VERSION 5.7 ;
BUSBITCHARS "[]" ;
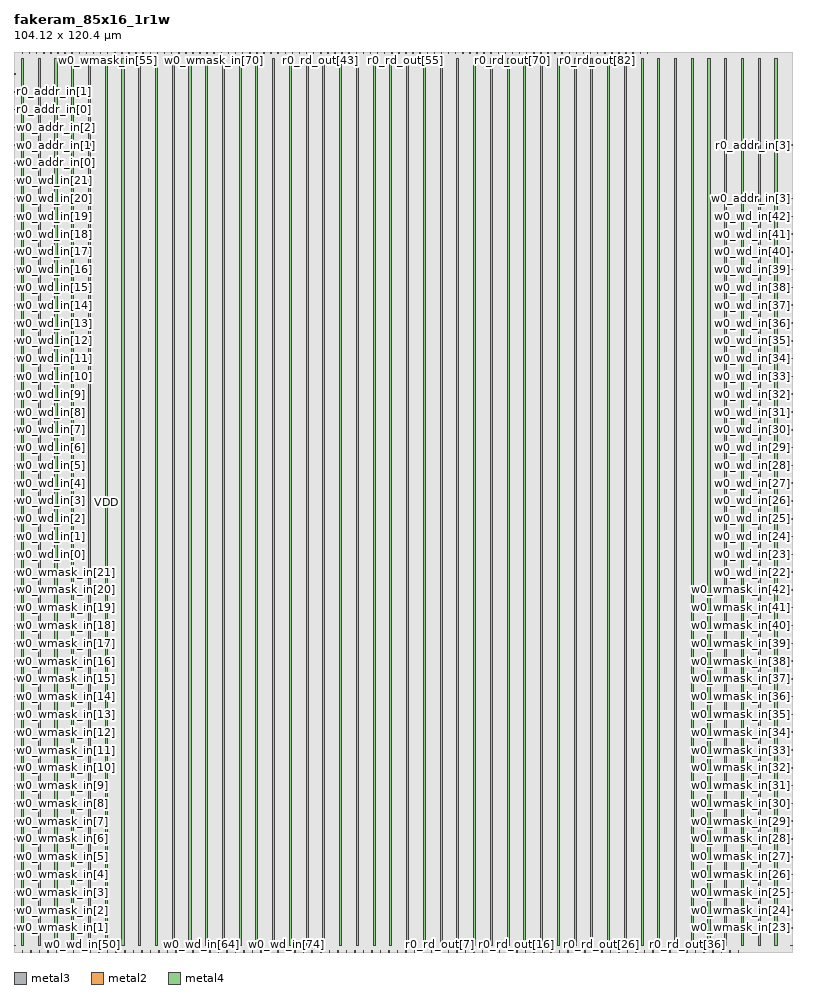
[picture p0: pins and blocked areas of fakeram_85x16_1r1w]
MACRO fakeram_85x16_1r1w
  FOREIGN fakeram_85x16_1r1w 0 0 ;
  SYMMETRY X Y R90 ;
  SIZE 104.120 BY 120.400 ;
  CLASS BLOCK ;
  PIN w0_wmask_in[0]
    DIRECTION INPUT ;
    USE SIGNAL ;
    SHAPE ABUTMENT ;
    PORT
      LAYER metal3 ;
      RECT 0.000 0.805 0.210 0.875 ;
    END
  END w0_wmask_in[0]
  PIN w0_wmask_in[1]
    DIRECTION INPUT ;
    USE SIGNAL ;
    SHAPE ABUTMENT ;
    PORT
      LAYER metal3 ;
      RECT 0.000 3.185 0.210 3.255 ;
    END
  END w0_wmask_in[1]
  PIN w0_wmask_in[2]
    DIRECTION INPUT ;
    USE SIGNAL ;
    SHAPE ABUTMENT ;
    PORT
      LAYER metal3 ;
      RECT 0.000 5.565 0.210 5.635 ;
    END
  END w0_wmask_in[2]
  PIN w0_wmask_in[3]
    DIRECTION INPUT ;
    USE SIGNAL ;
    SHAPE ABUTMENT ;
    PORT
      LAYER metal3 ;
      RECT 0.000 7.945 0.210 8.015 ;
    END
  END w0_wmask_in[3]
  PIN w0_wmask_in[4]
    DIRECTION INPUT ;
    USE SIGNAL ;
    SHAPE ABUTMENT ;
    PORT
      LAYER metal3 ;
      RECT 0.000 10.325 0.210 10.395 ;
    END
  END w0_wmask_in[4]
  PIN w0_wmask_in[5]
    DIRECTION INPUT ;
    USE SIGNAL ;
    SHAPE ABUTMENT ;
    PORT
      LAYER metal3 ;
      RECT 0.000 12.705 0.210 12.775 ;
    END
  END w0_wmask_in[5]
  PIN w0_wmask_in[6]
    DIRECTION INPUT ;
    USE SIGNAL ;
    SHAPE ABUTMENT ;
    PORT
      LAYER metal3 ;
      RECT 0.000 15.085 0.210 15.155 ;
    END
  END w0_wmask_in[6]
  PIN w0_wmask_in[7]
    DIRECTION INPUT ;
    USE SIGNAL ;
    SHAPE ABUTMENT ;
    PORT
      LAYER metal3 ;
      RECT 0.000 17.465 0.210 17.535 ;
    END
  END w0_wmask_in[7]
  PIN w0_wmask_in[8]
    DIRECTION INPUT ;
    USE SIGNAL ;
    SHAPE ABUTMENT ;
    PORT
      LAYER metal3 ;
      RECT 0.000 19.845 0.210 19.915 ;
    END
  END w0_wmask_in[8]
  PIN w0_wmask_in[9]
    DIRECTION INPUT ;
    USE SIGNAL ;
    SHAPE ABUTMENT ;
    PORT
      LAYER metal3 ;
      RECT 0.000 22.225 0.210 22.295 ;
    END
  END w0_wmask_in[9]
  PIN w0_wmask_in[10]
    DIRECTION INPUT ;
    USE SIGNAL ;
    SHAPE ABUTMENT ;
    PORT
      LAYER metal3 ;
      RECT 0.000 24.605 0.210 24.675 ;
    END
  END w0_wmask_in[10]
  PIN w0_wmask_in[11]
    DIRECTION INPUT ;
    USE SIGNAL ;
    SHAPE ABUTMENT ;
    PORT
      LAYER metal3 ;
      RECT 0.000 26.985 0.210 27.055 ;
    END
  END w0_wmask_in[11]
  PIN w0_wmask_in[12]
    DIRECTION INPUT ;
    USE SIGNAL ;
    SHAPE ABUTMENT ;
    PORT
      LAYER metal3 ;
      RECT 0.000 29.365 0.210 29.435 ;
    END
  END w0_wmask_in[12]
  PIN w0_wmask_in[13]
    DIRECTION INPUT ;
    USE SIGNAL ;
    SHAPE ABUTMENT ;
    PORT
      LAYER metal3 ;
      RECT 0.000 31.745 0.210 31.815 ;
    END
  END w0_wmask_in[13]
  PIN w0_wmask_in[14]
    DIRECTION INPUT ;
    USE SIGNAL ;
    SHAPE ABUTMENT ;
    PORT
      LAYER metal3 ;
      RECT 0.000 34.125 0.210 34.195 ;
    END
  END w0_wmask_in[14]
  PIN w0_wmask_in[15]
    DIRECTION INPUT ;
    USE SIGNAL ;
    SHAPE ABUTMENT ;
    PORT
      LAYER metal3 ;
      RECT 0.000 36.505 0.210 36.575 ;
    END
  END w0_wmask_in[15]
  PIN w0_wmask_in[16]
    DIRECTION INPUT ;
    USE SIGNAL ;
    SHAPE ABUTMENT ;
    PORT
      LAYER metal3 ;
      RECT 0.000 38.885 0.210 38.955 ;
    END
  END w0_wmask_in[16]
  PIN w0_wmask_in[17]
    DIRECTION INPUT ;
    USE SIGNAL ;
    SHAPE ABUTMENT ;
    PORT
      LAYER metal3 ;
      RECT 0.000 41.265 0.210 41.335 ;
    END
  END w0_wmask_in[17]
  PIN w0_wmask_in[18]
    DIRECTION INPUT ;
    USE SIGNAL ;
    SHAPE ABUTMENT ;
    PORT
      LAYER metal3 ;
      RECT 0.000 43.645 0.210 43.715 ;
    END
  END w0_wmask_in[18]
  PIN w0_wmask_in[19]
    DIRECTION INPUT ;
    USE SIGNAL ;
    SHAPE ABUTMENT ;
    PORT
      LAYER metal3 ;
      RECT 0.000 46.025 0.210 46.095 ;
    END
  END w0_wmask_in[19]
  PIN w0_wmask_in[20]
    DIRECTION INPUT ;
    USE SIGNAL ;
    SHAPE ABUTMENT ;
    PORT
      LAYER metal3 ;
      RECT 0.000 48.405 0.210 48.475 ;
    END
  END w0_wmask_in[20]
  PIN w0_wmask_in[21]
    DIRECTION INPUT ;
    USE SIGNAL ;
    SHAPE ABUTMENT ;
    PORT
      LAYER metal3 ;
      RECT 0.000 50.785 0.210 50.855 ;
    END
  END w0_wmask_in[21]
  PIN w0_wmask_in[22]
    DIRECTION INPUT ;
    USE SIGNAL ;
    SHAPE ABUTMENT ;
    PORT
      LAYER metal3 ;
      RECT 103.910 0.805 104.120 0.875 ;
    END
  END w0_wmask_in[22]
  PIN w0_wmask_in[23]
    DIRECTION INPUT ;
    USE SIGNAL ;
    SHAPE ABUTMENT ;
    PORT
      LAYER metal3 ;
      RECT 103.910 3.185 104.120 3.255 ;
    END
  END w0_wmask_in[23]
  PIN w0_wmask_in[24]
    DIRECTION INPUT ;
    USE SIGNAL ;
    SHAPE ABUTMENT ;
    PORT
      LAYER metal3 ;
      RECT 103.910 5.565 104.120 5.635 ;
    END
  END w0_wmask_in[24]
  PIN w0_wmask_in[25]
    DIRECTION INPUT ;
    USE SIGNAL ;
    SHAPE ABUTMENT ;
    PORT
      LAYER metal3 ;
      RECT 103.910 7.945 104.120 8.015 ;
    END
  END w0_wmask_in[25]
  PIN w0_wmask_in[26]
    DIRECTION INPUT ;
    USE SIGNAL ;
    SHAPE ABUTMENT ;
    PORT
      LAYER metal3 ;
      RECT 103.910 10.325 104.120 10.395 ;
    END
  END w0_wmask_in[26]
  PIN w0_wmask_in[27]
    DIRECTION INPUT ;
    USE SIGNAL ;
    SHAPE ABUTMENT ;
    PORT
      LAYER metal3 ;
      RECT 103.910 12.705 104.120 12.775 ;
    END
  END w0_wmask_in[27]
  PIN w0_wmask_in[28]
    DIRECTION INPUT ;
    USE SIGNAL ;
    SHAPE ABUTMENT ;
    PORT
      LAYER metal3 ;
      RECT 103.910 15.085 104.120 15.155 ;
    END
  END w0_wmask_in[28]
  PIN w0_wmask_in[29]
    DIRECTION INPUT ;
    USE SIGNAL ;
    SHAPE ABUTMENT ;
    PORT
      LAYER metal3 ;
      RECT 103.910 17.465 104.120 17.535 ;
    END
  END w0_wmask_in[29]
  PIN w0_wmask_in[30]
    DIRECTION INPUT ;
    USE SIGNAL ;
    SHAPE ABUTMENT ;
    PORT
      LAYER metal3 ;
      RECT 103.910 19.845 104.120 19.915 ;
    END
  END w0_wmask_in[30]
  PIN w0_wmask_in[31]
    DIRECTION INPUT ;
    USE SIGNAL ;
    SHAPE ABUTMENT ;
    PORT
      LAYER metal3 ;
      RECT 103.910 22.225 104.120 22.295 ;
    END
  END w0_wmask_in[31]
  PIN w0_wmask_in[32]
    DIRECTION INPUT ;
    USE SIGNAL ;
    SHAPE ABUTMENT ;
    PORT
      LAYER metal3 ;
      RECT 103.910 24.605 104.120 24.675 ;
    END
  END w0_wmask_in[32]
  PIN w0_wmask_in[33]
    DIRECTION INPUT ;
    USE SIGNAL ;
    SHAPE ABUTMENT ;
    PORT
      LAYER metal3 ;
      RECT 103.910 26.985 104.120 27.055 ;
    END
  END w0_wmask_in[33]
  PIN w0_wmask_in[34]
    DIRECTION INPUT ;
    USE SIGNAL ;
    SHAPE ABUTMENT ;
    PORT
      LAYER metal3 ;
      RECT 103.910 29.365 104.120 29.435 ;
    END
  END w0_wmask_in[34]
  PIN w0_wmask_in[35]
    DIRECTION INPUT ;
    USE SIGNAL ;
    SHAPE ABUTMENT ;
    PORT
      LAYER metal3 ;
      RECT 103.910 31.745 104.120 31.815 ;
    END
  END w0_wmask_in[35]
  PIN w0_wmask_in[36]
    DIRECTION INPUT ;
    USE SIGNAL ;
    SHAPE ABUTMENT ;
    PORT
      LAYER metal3 ;
      RECT 103.910 34.125 104.120 34.195 ;
    END
  END w0_wmask_in[36]
  PIN w0_wmask_in[37]
    DIRECTION INPUT ;
    USE SIGNAL ;
    SHAPE ABUTMENT ;
    PORT
      LAYER metal3 ;
      RECT 103.910 36.505 104.120 36.575 ;
    END
  END w0_wmask_in[37]
  PIN w0_wmask_in[38]
    DIRECTION INPUT ;
    USE SIGNAL ;
    SHAPE ABUTMENT ;
    PORT
      LAYER metal3 ;
      RECT 103.910 38.885 104.120 38.955 ;
    END
  END w0_wmask_in[38]
  PIN w0_wmask_in[39]
    DIRECTION INPUT ;
    USE SIGNAL ;
    SHAPE ABUTMENT ;
    PORT
      LAYER metal3 ;
      RECT 103.910 41.265 104.120 41.335 ;
    END
  END w0_wmask_in[39]
  PIN w0_wmask_in[40]
    DIRECTION INPUT ;
    USE SIGNAL ;
    SHAPE ABUTMENT ;
    PORT
      LAYER metal3 ;
      RECT 103.910 43.645 104.120 43.715 ;
    END
  END w0_wmask_in[40]
  PIN w0_wmask_in[41]
    DIRECTION INPUT ;
    USE SIGNAL ;
    SHAPE ABUTMENT ;
    PORT
      LAYER metal3 ;
      RECT 103.910 46.025 104.120 46.095 ;
    END
  END w0_wmask_in[41]
  PIN w0_wmask_in[42]
    DIRECTION INPUT ;
    USE SIGNAL ;
    SHAPE ABUTMENT ;
    PORT
      LAYER metal3 ;
      RECT 103.910 48.405 104.120 48.475 ;
    END
  END w0_wmask_in[42]
  PIN w0_wmask_in[43]
    DIRECTION INPUT ;
    USE SIGNAL ;
    SHAPE ABUTMENT ;
    PORT
      LAYER metal2 ;
      RECT 1.105 120.190 1.175 120.400 ;
    END
  END w0_wmask_in[43]
  PIN w0_wmask_in[44]
    DIRECTION INPUT ;
    USE SIGNAL ;
    SHAPE ABUTMENT ;
    PORT
      LAYER metal2 ;
      RECT 2.055 120.190 2.125 120.400 ;
    END
  END w0_wmask_in[44]
  PIN w0_wmask_in[45]
    DIRECTION INPUT ;
    USE SIGNAL ;
    SHAPE ABUTMENT ;
    PORT
      LAYER metal2 ;
      RECT 3.005 120.190 3.075 120.400 ;
    END
  END w0_wmask_in[45]
  PIN w0_wmask_in[46]
    DIRECTION INPUT ;
    USE SIGNAL ;
    SHAPE ABUTMENT ;
    PORT
      LAYER metal2 ;
      RECT 3.955 120.190 4.025 120.400 ;
    END
  END w0_wmask_in[46]
  PIN w0_wmask_in[47]
    DIRECTION INPUT ;
    USE SIGNAL ;
    SHAPE ABUTMENT ;
    PORT
      LAYER metal2 ;
      RECT 4.905 120.190 4.975 120.400 ;
    END
  END w0_wmask_in[47]
  PIN w0_wmask_in[48]
    DIRECTION INPUT ;
    USE SIGNAL ;
    SHAPE ABUTMENT ;
    PORT
      LAYER metal2 ;
      RECT 5.855 120.190 5.925 120.400 ;
    END
  END w0_wmask_in[48]
  PIN w0_wmask_in[49]
    DIRECTION INPUT ;
    USE SIGNAL ;
    SHAPE ABUTMENT ;
    PORT
      LAYER metal2 ;
      RECT 6.805 120.190 6.875 120.400 ;
    END
  END w0_wmask_in[49]
  PIN w0_wmask_in[50]
    DIRECTION INPUT ;
    USE SIGNAL ;
    SHAPE ABUTMENT ;
    PORT
      LAYER metal2 ;
      RECT 7.755 120.190 7.825 120.400 ;
    END
  END w0_wmask_in[50]
  PIN w0_wmask_in[51]
    DIRECTION INPUT ;
    USE SIGNAL ;
    SHAPE ABUTMENT ;
    PORT
      LAYER metal2 ;
      RECT 8.705 120.190 8.775 120.400 ;
    END
  END w0_wmask_in[51]
  PIN w0_wmask_in[52]
    DIRECTION INPUT ;
    USE SIGNAL ;
    SHAPE ABUTMENT ;
    PORT
      LAYER metal2 ;
      RECT 9.655 120.190 9.725 120.400 ;
    END
  END w0_wmask_in[52]
  PIN w0_wmask_in[53]
    DIRECTION INPUT ;
    USE SIGNAL ;
    SHAPE ABUTMENT ;
    PORT
      LAYER metal2 ;
      RECT 10.605 120.190 10.675 120.400 ;
    END
  END w0_wmask_in[53]
  PIN w0_wmask_in[54]
    DIRECTION INPUT ;
    USE SIGNAL ;
    SHAPE ABUTMENT ;
    PORT
      LAYER metal2 ;
      RECT 11.555 120.190 11.625 120.400 ;
    END
  END w0_wmask_in[54]
  PIN w0_wmask_in[55]
    DIRECTION INPUT ;
    USE SIGNAL ;
    SHAPE ABUTMENT ;
    PORT
      LAYER metal2 ;
      RECT 12.505 120.190 12.575 120.400 ;
    END
  END w0_wmask_in[55]
  PIN w0_wmask_in[56]
    DIRECTION INPUT ;
    USE SIGNAL ;
    SHAPE ABUTMENT ;
    PORT
      LAYER metal2 ;
      RECT 13.455 120.190 13.525 120.400 ;
    END
  END w0_wmask_in[56]
  PIN w0_wmask_in[57]
    DIRECTION INPUT ;
    USE SIGNAL ;
    SHAPE ABUTMENT ;
    PORT
      LAYER metal2 ;
      RECT 14.405 120.190 14.475 120.400 ;
    END
  END w0_wmask_in[57]
  PIN w0_wmask_in[58]
    DIRECTION INPUT ;
    USE SIGNAL ;
    SHAPE ABUTMENT ;
    PORT
      LAYER metal2 ;
      RECT 15.355 120.190 15.425 120.400 ;
    END
  END w0_wmask_in[58]
  PIN w0_wmask_in[59]
    DIRECTION INPUT ;
    USE SIGNAL ;
    SHAPE ABUTMENT ;
    PORT
      LAYER metal2 ;
      RECT 16.305 120.190 16.375 120.400 ;
    END
  END w0_wmask_in[59]
  PIN w0_wmask_in[60]
    DIRECTION INPUT ;
    USE SIGNAL ;
    SHAPE ABUTMENT ;
    PORT
      LAYER metal2 ;
      RECT 17.255 120.190 17.325 120.400 ;
    END
  END w0_wmask_in[60]
  PIN w0_wmask_in[61]
    DIRECTION INPUT ;
    USE SIGNAL ;
    SHAPE ABUTMENT ;
    PORT
      LAYER metal2 ;
      RECT 18.205 120.190 18.275 120.400 ;
    END
  END w0_wmask_in[61]
  PIN w0_wmask_in[62]
    DIRECTION INPUT ;
    USE SIGNAL ;
    SHAPE ABUTMENT ;
    PORT
      LAYER metal2 ;
      RECT 19.155 120.190 19.225 120.400 ;
    END
  END w0_wmask_in[62]
  PIN w0_wmask_in[63]
    DIRECTION INPUT ;
    USE SIGNAL ;
    SHAPE ABUTMENT ;
    PORT
      LAYER metal2 ;
      RECT 20.105 120.190 20.175 120.400 ;
    END
  END w0_wmask_in[63]
  PIN w0_wmask_in[64]
    DIRECTION INPUT ;
    USE SIGNAL ;
    SHAPE ABUTMENT ;
    PORT
      LAYER metal2 ;
      RECT 21.055 120.190 21.125 120.400 ;
    END
  END w0_wmask_in[64]
  PIN w0_wmask_in[65]
    DIRECTION INPUT ;
    USE SIGNAL ;
    SHAPE ABUTMENT ;
    PORT
      LAYER metal2 ;
      RECT 22.005 120.190 22.075 120.400 ;
    END
  END w0_wmask_in[65]
  PIN w0_wmask_in[66]
    DIRECTION INPUT ;
    USE SIGNAL ;
    SHAPE ABUTMENT ;
    PORT
      LAYER metal2 ;
      RECT 22.955 120.190 23.025 120.400 ;
    END
  END w0_wmask_in[66]
  PIN w0_wmask_in[67]
    DIRECTION INPUT ;
    USE SIGNAL ;
    SHAPE ABUTMENT ;
    PORT
      LAYER metal2 ;
      RECT 23.905 120.190 23.975 120.400 ;
    END
  END w0_wmask_in[67]
  PIN w0_wmask_in[68]
    DIRECTION INPUT ;
    USE SIGNAL ;
    SHAPE ABUTMENT ;
    PORT
      LAYER metal2 ;
      RECT 24.855 120.190 24.925 120.400 ;
    END
  END w0_wmask_in[68]
  PIN w0_wmask_in[69]
    DIRECTION INPUT ;
    USE SIGNAL ;
    SHAPE ABUTMENT ;
    PORT
      LAYER metal2 ;
      RECT 25.805 120.190 25.875 120.400 ;
    END
  END w0_wmask_in[69]
  PIN w0_wmask_in[70]
    DIRECTION INPUT ;
    USE SIGNAL ;
    SHAPE ABUTMENT ;
    PORT
      LAYER metal2 ;
      RECT 26.755 120.190 26.825 120.400 ;
    END
  END w0_wmask_in[70]
  PIN w0_wmask_in[71]
    DIRECTION INPUT ;
    USE SIGNAL ;
    SHAPE ABUTMENT ;
    PORT
      LAYER metal2 ;
      RECT 27.705 120.190 27.775 120.400 ;
    END
  END w0_wmask_in[71]
  PIN w0_wmask_in[72]
    DIRECTION INPUT ;
    USE SIGNAL ;
    SHAPE ABUTMENT ;
    PORT
      LAYER metal2 ;
      RECT 28.655 120.190 28.725 120.400 ;
    END
  END w0_wmask_in[72]
  PIN w0_wmask_in[73]
    DIRECTION INPUT ;
    USE SIGNAL ;
    SHAPE ABUTMENT ;
    PORT
      LAYER metal2 ;
      RECT 29.605 120.190 29.675 120.400 ;
    END
  END w0_wmask_in[73]
  PIN w0_wmask_in[74]
    DIRECTION INPUT ;
    USE SIGNAL ;
    SHAPE ABUTMENT ;
    PORT
      LAYER metal2 ;
      RECT 30.555 120.190 30.625 120.400 ;
    END
  END w0_wmask_in[74]
  PIN w0_wmask_in[75]
    DIRECTION INPUT ;
    USE SIGNAL ;
    SHAPE ABUTMENT ;
    PORT
      LAYER metal2 ;
      RECT 31.505 120.190 31.575 120.400 ;
    END
  END w0_wmask_in[75]
  PIN w0_wmask_in[76]
    DIRECTION INPUT ;
    USE SIGNAL ;
    SHAPE ABUTMENT ;
    PORT
      LAYER metal2 ;
      RECT 32.455 120.190 32.525 120.400 ;
    END
  END w0_wmask_in[76]
  PIN w0_wmask_in[77]
    DIRECTION INPUT ;
    USE SIGNAL ;
    SHAPE ABUTMENT ;
    PORT
      LAYER metal2 ;
      RECT 33.405 120.190 33.475 120.400 ;
    END
  END w0_wmask_in[77]
  PIN w0_wmask_in[78]
    DIRECTION INPUT ;
    USE SIGNAL ;
    SHAPE ABUTMENT ;
    PORT
      LAYER metal2 ;
      RECT 34.355 120.190 34.425 120.400 ;
    END
  END w0_wmask_in[78]
  PIN w0_wmask_in[79]
    DIRECTION INPUT ;
    USE SIGNAL ;
    SHAPE ABUTMENT ;
    PORT
      LAYER metal2 ;
      RECT 35.305 120.190 35.375 120.400 ;
    END
  END w0_wmask_in[79]
  PIN w0_wmask_in[80]
    DIRECTION INPUT ;
    USE SIGNAL ;
    SHAPE ABUTMENT ;
    PORT
      LAYER metal2 ;
      RECT 36.255 120.190 36.325 120.400 ;
    END
  END w0_wmask_in[80]
  PIN w0_wmask_in[81]
    DIRECTION INPUT ;
    USE SIGNAL ;
    SHAPE ABUTMENT ;
    PORT
      LAYER metal2 ;
      RECT 37.205 120.190 37.275 120.400 ;
    END
  END w0_wmask_in[81]
  PIN w0_wmask_in[82]
    DIRECTION INPUT ;
    USE SIGNAL ;
    SHAPE ABUTMENT ;
    PORT
      LAYER metal2 ;
      RECT 38.155 120.190 38.225 120.400 ;
    END
  END w0_wmask_in[82]
  PIN w0_wmask_in[83]
    DIRECTION INPUT ;
    USE SIGNAL ;
    SHAPE ABUTMENT ;
    PORT
      LAYER metal2 ;
      RECT 39.105 120.190 39.175 120.400 ;
    END
  END w0_wmask_in[83]
  PIN w0_wmask_in[84]
    DIRECTION INPUT ;
    USE SIGNAL ;
    SHAPE ABUTMENT ;
    PORT
      LAYER metal2 ;
      RECT 40.055 120.190 40.125 120.400 ;
    END
  END w0_wmask_in[84]
  PIN w0_wd_in[0]
    DIRECTION INPUT ;
    USE SIGNAL ;
    SHAPE ABUTMENT ;
    PORT
      LAYER metal3 ;
      RECT 0.000 53.165 0.210 53.235 ;
    END
  END w0_wd_in[0]
  PIN w0_wd_in[1]
    DIRECTION INPUT ;
    USE SIGNAL ;
    SHAPE ABUTMENT ;
    PORT
      LAYER metal3 ;
      RECT 0.000 55.545 0.210 55.615 ;
    END
  END w0_wd_in[1]
  PIN w0_wd_in[2]
    DIRECTION INPUT ;
    USE SIGNAL ;
    SHAPE ABUTMENT ;
    PORT
      LAYER metal3 ;
      RECT 0.000 57.925 0.210 57.995 ;
    END
  END w0_wd_in[2]
  PIN w0_wd_in[3]
    DIRECTION INPUT ;
    USE SIGNAL ;
    SHAPE ABUTMENT ;
    PORT
      LAYER metal3 ;
      RECT 0.000 60.305 0.210 60.375 ;
    END
  END w0_wd_in[3]
  PIN w0_wd_in[4]
    DIRECTION INPUT ;
    USE SIGNAL ;
    SHAPE ABUTMENT ;
    PORT
      LAYER metal3 ;
      RECT 0.000 62.685 0.210 62.755 ;
    END
  END w0_wd_in[4]
  PIN w0_wd_in[5]
    DIRECTION INPUT ;
    USE SIGNAL ;
    SHAPE ABUTMENT ;
    PORT
      LAYER metal3 ;
      RECT 0.000 65.065 0.210 65.135 ;
    END
  END w0_wd_in[5]
  PIN w0_wd_in[6]
    DIRECTION INPUT ;
    USE SIGNAL ;
    SHAPE ABUTMENT ;
    PORT
      LAYER metal3 ;
      RECT 0.000 67.445 0.210 67.515 ;
    END
  END w0_wd_in[6]
  PIN w0_wd_in[7]
    DIRECTION INPUT ;
    USE SIGNAL ;
    SHAPE ABUTMENT ;
    PORT
      LAYER metal3 ;
      RECT 0.000 69.825 0.210 69.895 ;
    END
  END w0_wd_in[7]
  PIN w0_wd_in[8]
    DIRECTION INPUT ;
    USE SIGNAL ;
    SHAPE ABUTMENT ;
    PORT
      LAYER metal3 ;
      RECT 0.000 72.205 0.210 72.275 ;
    END
  END w0_wd_in[8]
  PIN w0_wd_in[9]
    DIRECTION INPUT ;
    USE SIGNAL ;
    SHAPE ABUTMENT ;
    PORT
      LAYER metal3 ;
      RECT 0.000 74.585 0.210 74.655 ;
    END
  END w0_wd_in[9]
  PIN w0_wd_in[10]
    DIRECTION INPUT ;
    USE SIGNAL ;
    SHAPE ABUTMENT ;
    PORT
      LAYER metal3 ;
      RECT 0.000 76.965 0.210 77.035 ;
    END
  END w0_wd_in[10]
  PIN w0_wd_in[11]
    DIRECTION INPUT ;
    USE SIGNAL ;
    SHAPE ABUTMENT ;
    PORT
      LAYER metal3 ;
      RECT 0.000 79.345 0.210 79.415 ;
    END
  END w0_wd_in[11]
  PIN w0_wd_in[12]
    DIRECTION INPUT ;
    USE SIGNAL ;
    SHAPE ABUTMENT ;
    PORT
      LAYER metal3 ;
      RECT 0.000 81.725 0.210 81.795 ;
    END
  END w0_wd_in[12]
  PIN w0_wd_in[13]
    DIRECTION INPUT ;
    USE SIGNAL ;
    SHAPE ABUTMENT ;
    PORT
      LAYER metal3 ;
      RECT 0.000 84.105 0.210 84.175 ;
    END
  END w0_wd_in[13]
  PIN w0_wd_in[14]
    DIRECTION INPUT ;
    USE SIGNAL ;
    SHAPE ABUTMENT ;
    PORT
      LAYER metal3 ;
      RECT 0.000 86.485 0.210 86.555 ;
    END
  END w0_wd_in[14]
  PIN w0_wd_in[15]
    DIRECTION INPUT ;
    USE SIGNAL ;
    SHAPE ABUTMENT ;
    PORT
      LAYER metal3 ;
      RECT 0.000 88.865 0.210 88.935 ;
    END
  END w0_wd_in[15]
  PIN w0_wd_in[16]
    DIRECTION INPUT ;
    USE SIGNAL ;
    SHAPE ABUTMENT ;
    PORT
      LAYER metal3 ;
      RECT 0.000 91.245 0.210 91.315 ;
    END
  END w0_wd_in[16]
  PIN w0_wd_in[17]
    DIRECTION INPUT ;
    USE SIGNAL ;
    SHAPE ABUTMENT ;
    PORT
      LAYER metal3 ;
      RECT 0.000 93.625 0.210 93.695 ;
    END
  END w0_wd_in[17]
  PIN w0_wd_in[18]
    DIRECTION INPUT ;
    USE SIGNAL ;
    SHAPE ABUTMENT ;
    PORT
      LAYER metal3 ;
      RECT 0.000 96.005 0.210 96.075 ;
    END
  END w0_wd_in[18]
  PIN w0_wd_in[19]
    DIRECTION INPUT ;
    USE SIGNAL ;
    SHAPE ABUTMENT ;
    PORT
      LAYER metal3 ;
      RECT 0.000 98.385 0.210 98.455 ;
    END
  END w0_wd_in[19]
  PIN w0_wd_in[20]
    DIRECTION INPUT ;
    USE SIGNAL ;
    SHAPE ABUTMENT ;
    PORT
      LAYER metal3 ;
      RECT 0.000 100.765 0.210 100.835 ;
    END
  END w0_wd_in[20]
  PIN w0_wd_in[21]
    DIRECTION INPUT ;
    USE SIGNAL ;
    SHAPE ABUTMENT ;
    PORT
      LAYER metal3 ;
      RECT 0.000 103.145 0.210 103.215 ;
    END
  END w0_wd_in[21]
  PIN w0_wd_in[22]
    DIRECTION INPUT ;
    USE SIGNAL ;
    SHAPE ABUTMENT ;
    PORT
      LAYER metal3 ;
      RECT 103.910 50.785 104.120 50.855 ;
    END
  END w0_wd_in[22]
  PIN w0_wd_in[23]
    DIRECTION INPUT ;
    USE SIGNAL ;
    SHAPE ABUTMENT ;
    PORT
      LAYER metal3 ;
      RECT 103.910 53.165 104.120 53.235 ;
    END
  END w0_wd_in[23]
  PIN w0_wd_in[24]
    DIRECTION INPUT ;
    USE SIGNAL ;
    SHAPE ABUTMENT ;
    PORT
      LAYER metal3 ;
      RECT 103.910 55.545 104.120 55.615 ;
    END
  END w0_wd_in[24]
  PIN w0_wd_in[25]
    DIRECTION INPUT ;
    USE SIGNAL ;
    SHAPE ABUTMENT ;
    PORT
      LAYER metal3 ;
      RECT 103.910 57.925 104.120 57.995 ;
    END
  END w0_wd_in[25]
  PIN w0_wd_in[26]
    DIRECTION INPUT ;
    USE SIGNAL ;
    SHAPE ABUTMENT ;
    PORT
      LAYER metal3 ;
      RECT 103.910 60.305 104.120 60.375 ;
    END
  END w0_wd_in[26]
  PIN w0_wd_in[27]
    DIRECTION INPUT ;
    USE SIGNAL ;
    SHAPE ABUTMENT ;
    PORT
      LAYER metal3 ;
      RECT 103.910 62.685 104.120 62.755 ;
    END
  END w0_wd_in[27]
  PIN w0_wd_in[28]
    DIRECTION INPUT ;
    USE SIGNAL ;
    SHAPE ABUTMENT ;
    PORT
      LAYER metal3 ;
      RECT 103.910 65.065 104.120 65.135 ;
    END
  END w0_wd_in[28]
  PIN w0_wd_in[29]
    DIRECTION INPUT ;
    USE SIGNAL ;
    SHAPE ABUTMENT ;
    PORT
      LAYER metal3 ;
      RECT 103.910 67.445 104.120 67.515 ;
    END
  END w0_wd_in[29]
  PIN w0_wd_in[30]
    DIRECTION INPUT ;
    USE SIGNAL ;
    SHAPE ABUTMENT ;
    PORT
      LAYER metal3 ;
      RECT 103.910 69.825 104.120 69.895 ;
    END
  END w0_wd_in[30]
  PIN w0_wd_in[31]
    DIRECTION INPUT ;
    USE SIGNAL ;
    SHAPE ABUTMENT ;
    PORT
      LAYER metal3 ;
      RECT 103.910 72.205 104.120 72.275 ;
    END
  END w0_wd_in[31]
  PIN w0_wd_in[32]
    DIRECTION INPUT ;
    USE SIGNAL ;
    SHAPE ABUTMENT ;
    PORT
      LAYER metal3 ;
      RECT 103.910 74.585 104.120 74.655 ;
    END
  END w0_wd_in[32]
  PIN w0_wd_in[33]
    DIRECTION INPUT ;
    USE SIGNAL ;
    SHAPE ABUTMENT ;
    PORT
      LAYER metal3 ;
      RECT 103.910 76.965 104.120 77.035 ;
    END
  END w0_wd_in[33]
  PIN w0_wd_in[34]
    DIRECTION INPUT ;
    USE SIGNAL ;
    SHAPE ABUTMENT ;
    PORT
      LAYER metal3 ;
      RECT 103.910 79.345 104.120 79.415 ;
    END
  END w0_wd_in[34]
  PIN w0_wd_in[35]
    DIRECTION INPUT ;
    USE SIGNAL ;
    SHAPE ABUTMENT ;
    PORT
      LAYER metal3 ;
      RECT 103.910 81.725 104.120 81.795 ;
    END
  END w0_wd_in[35]
  PIN w0_wd_in[36]
    DIRECTION INPUT ;
    USE SIGNAL ;
    SHAPE ABUTMENT ;
    PORT
      LAYER metal3 ;
      RECT 103.910 84.105 104.120 84.175 ;
    END
  END w0_wd_in[36]
  PIN w0_wd_in[37]
    DIRECTION INPUT ;
    USE SIGNAL ;
    SHAPE ABUTMENT ;
    PORT
      LAYER metal3 ;
      RECT 103.910 86.485 104.120 86.555 ;
    END
  END w0_wd_in[37]
  PIN w0_wd_in[38]
    DIRECTION INPUT ;
    USE SIGNAL ;
    SHAPE ABUTMENT ;
    PORT
      LAYER metal3 ;
      RECT 103.910 88.865 104.120 88.935 ;
    END
  END w0_wd_in[38]
  PIN w0_wd_in[39]
    DIRECTION INPUT ;
    USE SIGNAL ;
    SHAPE ABUTMENT ;
    PORT
      LAYER metal3 ;
      RECT 103.910 91.245 104.120 91.315 ;
    END
  END w0_wd_in[39]
  PIN w0_wd_in[40]
    DIRECTION INPUT ;
    USE SIGNAL ;
    SHAPE ABUTMENT ;
    PORT
      LAYER metal3 ;
      RECT 103.910 93.625 104.120 93.695 ;
    END
  END w0_wd_in[40]
  PIN w0_wd_in[41]
    DIRECTION INPUT ;
    USE SIGNAL ;
    SHAPE ABUTMENT ;
    PORT
      LAYER metal3 ;
      RECT 103.910 96.005 104.120 96.075 ;
    END
  END w0_wd_in[41]
  PIN w0_wd_in[42]
    DIRECTION INPUT ;
    USE SIGNAL ;
    SHAPE ABUTMENT ;
    PORT
      LAYER metal3 ;
      RECT 103.910 98.385 104.120 98.455 ;
    END
  END w0_wd_in[42]
  PIN w0_wd_in[43]
    DIRECTION OUTPUT ;
    USE SIGNAL ;
    SHAPE ABUTMENT ;
    PORT
      LAYER metal2 ;
      RECT 1.105 0.000 1.175 0.210 ;
    END
  END w0_wd_in[43]
  PIN w0_wd_in[44]
    DIRECTION OUTPUT ;
    USE SIGNAL ;
    SHAPE ABUTMENT ;
    PORT
      LAYER metal2 ;
      RECT 2.245 0.000 2.315 0.210 ;
    END
  END w0_wd_in[44]
  PIN w0_wd_in[45]
    DIRECTION OUTPUT ;
    USE SIGNAL ;
    SHAPE ABUTMENT ;
    PORT
      LAYER metal2 ;
      RECT 3.385 0.000 3.455 0.210 ;
    END
  END w0_wd_in[45]
  PIN w0_wd_in[46]
    DIRECTION OUTPUT ;
    USE SIGNAL ;
    SHAPE ABUTMENT ;
    PORT
      LAYER metal2 ;
      RECT 4.525 0.000 4.595 0.210 ;
    END
  END w0_wd_in[46]
  PIN w0_wd_in[47]
    DIRECTION OUTPUT ;
    USE SIGNAL ;
    SHAPE ABUTMENT ;
    PORT
      LAYER metal2 ;
      RECT 5.665 0.000 5.735 0.210 ;
    END
  END w0_wd_in[47]
  PIN w0_wd_in[48]
    DIRECTION OUTPUT ;
    USE SIGNAL ;
    SHAPE ABUTMENT ;
    PORT
      LAYER metal2 ;
      RECT 6.805 0.000 6.875 0.210 ;
    END
  END w0_wd_in[48]
  PIN w0_wd_in[49]
    DIRECTION OUTPUT ;
    USE SIGNAL ;
    SHAPE ABUTMENT ;
    PORT
      LAYER metal2 ;
      RECT 7.945 0.000 8.015 0.210 ;
    END
  END w0_wd_in[49]
  PIN w0_wd_in[50]
    DIRECTION OUTPUT ;
    USE SIGNAL ;
    SHAPE ABUTMENT ;
    PORT
      LAYER metal2 ;
      RECT 9.085 0.000 9.155 0.210 ;
    END
  END w0_wd_in[50]
  PIN w0_wd_in[51]
    DIRECTION OUTPUT ;
    USE SIGNAL ;
    SHAPE ABUTMENT ;
    PORT
      LAYER metal2 ;
      RECT 10.225 0.000 10.295 0.210 ;
    END
  END w0_wd_in[51]
  PIN w0_wd_in[52]
    DIRECTION OUTPUT ;
    USE SIGNAL ;
    SHAPE ABUTMENT ;
    PORT
      LAYER metal2 ;
      RECT 11.365 0.000 11.435 0.210 ;
    END
  END w0_wd_in[52]
  PIN w0_wd_in[53]
    DIRECTION OUTPUT ;
    USE SIGNAL ;
    SHAPE ABUTMENT ;
    PORT
      LAYER metal2 ;
      RECT 12.505 0.000 12.575 0.210 ;
    END
  END w0_wd_in[53]
  PIN w0_wd_in[54]
    DIRECTION OUTPUT ;
    USE SIGNAL ;
    SHAPE ABUTMENT ;
    PORT
      LAYER metal2 ;
      RECT 13.645 0.000 13.715 0.210 ;
    END
  END w0_wd_in[54]
  PIN w0_wd_in[55]
    DIRECTION OUTPUT ;
    USE SIGNAL ;
    SHAPE ABUTMENT ;
    PORT
      LAYER metal2 ;
      RECT 14.785 0.000 14.855 0.210 ;
    END
  END w0_wd_in[55]
  PIN w0_wd_in[56]
    DIRECTION OUTPUT ;
    USE SIGNAL ;
    SHAPE ABUTMENT ;
    PORT
      LAYER metal2 ;
      RECT 15.925 0.000 15.995 0.210 ;
    END
  END w0_wd_in[56]
  PIN w0_wd_in[57]
    DIRECTION OUTPUT ;
    USE SIGNAL ;
    SHAPE ABUTMENT ;
    PORT
      LAYER metal2 ;
      RECT 17.065 0.000 17.135 0.210 ;
    END
  END w0_wd_in[57]
  PIN w0_wd_in[58]
    DIRECTION OUTPUT ;
    USE SIGNAL ;
    SHAPE ABUTMENT ;
    PORT
      LAYER metal2 ;
      RECT 18.205 0.000 18.275 0.210 ;
    END
  END w0_wd_in[58]
  PIN w0_wd_in[59]
    DIRECTION OUTPUT ;
    USE SIGNAL ;
    SHAPE ABUTMENT ;
    PORT
      LAYER metal2 ;
      RECT 19.345 0.000 19.415 0.210 ;
    END
  END w0_wd_in[59]
  PIN w0_wd_in[60]
    DIRECTION OUTPUT ;
    USE SIGNAL ;
    SHAPE ABUTMENT ;
    PORT
      LAYER metal2 ;
      RECT 20.485 0.000 20.555 0.210 ;
    END
  END w0_wd_in[60]
  PIN w0_wd_in[61]
    DIRECTION OUTPUT ;
    USE SIGNAL ;
    SHAPE ABUTMENT ;
    PORT
      LAYER metal2 ;
      RECT 21.625 0.000 21.695 0.210 ;
    END
  END w0_wd_in[61]
  PIN w0_wd_in[62]
    DIRECTION OUTPUT ;
    USE SIGNAL ;
    SHAPE ABUTMENT ;
    PORT
      LAYER metal2 ;
      RECT 22.765 0.000 22.835 0.210 ;
    END
  END w0_wd_in[62]
  PIN w0_wd_in[63]
    DIRECTION OUTPUT ;
    USE SIGNAL ;
    SHAPE ABUTMENT ;
    PORT
      LAYER metal2 ;
      RECT 23.905 0.000 23.975 0.210 ;
    END
  END w0_wd_in[63]
  PIN w0_wd_in[64]
    DIRECTION OUTPUT ;
    USE SIGNAL ;
    SHAPE ABUTMENT ;
    PORT
      LAYER metal2 ;
      RECT 25.045 0.000 25.115 0.210 ;
    END
  END w0_wd_in[64]
  PIN w0_wd_in[65]
    DIRECTION OUTPUT ;
    USE SIGNAL ;
    SHAPE ABUTMENT ;
    PORT
      LAYER metal2 ;
      RECT 26.185 0.000 26.255 0.210 ;
    END
  END w0_wd_in[65]
  PIN w0_wd_in[66]
    DIRECTION OUTPUT ;
    USE SIGNAL ;
    SHAPE ABUTMENT ;
    PORT
      LAYER metal2 ;
      RECT 27.325 0.000 27.395 0.210 ;
    END
  END w0_wd_in[66]
  PIN w0_wd_in[67]
    DIRECTION OUTPUT ;
    USE SIGNAL ;
    SHAPE ABUTMENT ;
    PORT
      LAYER metal2 ;
      RECT 28.465 0.000 28.535 0.210 ;
    END
  END w0_wd_in[67]
  PIN w0_wd_in[68]
    DIRECTION OUTPUT ;
    USE SIGNAL ;
    SHAPE ABUTMENT ;
    PORT
      LAYER metal2 ;
      RECT 29.605 0.000 29.675 0.210 ;
    END
  END w0_wd_in[68]
  PIN w0_wd_in[69]
    DIRECTION OUTPUT ;
    USE SIGNAL ;
    SHAPE ABUTMENT ;
    PORT
      LAYER metal2 ;
      RECT 30.745 0.000 30.815 0.210 ;
    END
  END w0_wd_in[69]
  PIN w0_wd_in[70]
    DIRECTION OUTPUT ;
    USE SIGNAL ;
    SHAPE ABUTMENT ;
    PORT
      LAYER metal2 ;
      RECT 31.885 0.000 31.955 0.210 ;
    END
  END w0_wd_in[70]
  PIN w0_wd_in[71]
    DIRECTION OUTPUT ;
    USE SIGNAL ;
    SHAPE ABUTMENT ;
    PORT
      LAYER metal2 ;
      RECT 33.025 0.000 33.095 0.210 ;
    END
  END w0_wd_in[71]
  PIN w0_wd_in[72]
    DIRECTION OUTPUT ;
    USE SIGNAL ;
    SHAPE ABUTMENT ;
    PORT
      LAYER metal2 ;
      RECT 34.165 0.000 34.235 0.210 ;
    END
  END w0_wd_in[72]
  PIN w0_wd_in[73]
    DIRECTION OUTPUT ;
    USE SIGNAL ;
    SHAPE ABUTMENT ;
    PORT
      LAYER metal2 ;
      RECT 35.305 0.000 35.375 0.210 ;
    END
  END w0_wd_in[73]
  PIN w0_wd_in[74]
    DIRECTION OUTPUT ;
    USE SIGNAL ;
    SHAPE ABUTMENT ;
    PORT
      LAYER metal2 ;
      RECT 36.445 0.000 36.515 0.210 ;
    END
  END w0_wd_in[74]
  PIN w0_wd_in[75]
    DIRECTION OUTPUT ;
    USE SIGNAL ;
    SHAPE ABUTMENT ;
    PORT
      LAYER metal2 ;
      RECT 37.585 0.000 37.655 0.210 ;
    END
  END w0_wd_in[75]
  PIN w0_wd_in[76]
    DIRECTION OUTPUT ;
    USE SIGNAL ;
    SHAPE ABUTMENT ;
    PORT
      LAYER metal2 ;
      RECT 38.725 0.000 38.795 0.210 ;
    END
  END w0_wd_in[76]
  PIN w0_wd_in[77]
    DIRECTION OUTPUT ;
    USE SIGNAL ;
    SHAPE ABUTMENT ;
    PORT
      LAYER metal2 ;
      RECT 39.865 0.000 39.935 0.210 ;
    END
  END w0_wd_in[77]
  PIN w0_wd_in[78]
    DIRECTION OUTPUT ;
    USE SIGNAL ;
    SHAPE ABUTMENT ;
    PORT
      LAYER metal2 ;
      RECT 41.005 0.000 41.075 0.210 ;
    END
  END w0_wd_in[78]
  PIN w0_wd_in[79]
    DIRECTION OUTPUT ;
    USE SIGNAL ;
    SHAPE ABUTMENT ;
    PORT
      LAYER metal2 ;
      RECT 42.145 0.000 42.215 0.210 ;
    END
  END w0_wd_in[79]
  PIN w0_wd_in[80]
    DIRECTION OUTPUT ;
    USE SIGNAL ;
    SHAPE ABUTMENT ;
    PORT
      LAYER metal2 ;
      RECT 43.285 0.000 43.355 0.210 ;
    END
  END w0_wd_in[80]
  PIN w0_wd_in[81]
    DIRECTION OUTPUT ;
    USE SIGNAL ;
    SHAPE ABUTMENT ;
    PORT
      LAYER metal2 ;
      RECT 44.425 0.000 44.495 0.210 ;
    END
  END w0_wd_in[81]
  PIN w0_wd_in[82]
    DIRECTION OUTPUT ;
    USE SIGNAL ;
    SHAPE ABUTMENT ;
    PORT
      LAYER metal2 ;
      RECT 45.565 0.000 45.635 0.210 ;
    END
  END w0_wd_in[82]
  PIN w0_wd_in[83]
    DIRECTION OUTPUT ;
    USE SIGNAL ;
    SHAPE ABUTMENT ;
    PORT
      LAYER metal2 ;
      RECT 46.705 0.000 46.775 0.210 ;
    END
  END w0_wd_in[83]
  PIN w0_wd_in[84]
    DIRECTION OUTPUT ;
    USE SIGNAL ;
    SHAPE ABUTMENT ;
    PORT
      LAYER metal2 ;
      RECT 47.845 0.000 47.915 0.210 ;
    END
  END w0_wd_in[84]
  PIN r0_rd_out[0]
    DIRECTION OUTPUT ;
    USE SIGNAL ;
    SHAPE ABUTMENT ;
    PORT
      LAYER metal2 ;
      RECT 48.985 0.000 49.055 0.210 ;
    END
  END r0_rd_out[0]
  PIN r0_rd_out[1]
    DIRECTION OUTPUT ;
    USE SIGNAL ;
    SHAPE ABUTMENT ;
    PORT
      LAYER metal2 ;
      RECT 50.125 0.000 50.195 0.210 ;
    END
  END r0_rd_out[1]
  PIN r0_rd_out[2]
    DIRECTION OUTPUT ;
    USE SIGNAL ;
    SHAPE ABUTMENT ;
    PORT
      LAYER metal2 ;
      RECT 51.265 0.000 51.335 0.210 ;
    END
  END r0_rd_out[2]
  PIN r0_rd_out[3]
    DIRECTION OUTPUT ;
    USE SIGNAL ;
    SHAPE ABUTMENT ;
    PORT
      LAYER metal2 ;
      RECT 52.405 0.000 52.475 0.210 ;
    END
  END r0_rd_out[3]
  PIN r0_rd_out[4]
    DIRECTION OUTPUT ;
    USE SIGNAL ;
    SHAPE ABUTMENT ;
    PORT
      LAYER metal2 ;
      RECT 53.545 0.000 53.615 0.210 ;
    END
  END r0_rd_out[4]
  PIN r0_rd_out[5]
    DIRECTION OUTPUT ;
    USE SIGNAL ;
    SHAPE ABUTMENT ;
    PORT
      LAYER metal2 ;
      RECT 54.685 0.000 54.755 0.210 ;
    END
  END r0_rd_out[5]
  PIN r0_rd_out[6]
    DIRECTION OUTPUT ;
    USE SIGNAL ;
    SHAPE ABUTMENT ;
    PORT
      LAYER metal2 ;
      RECT 55.825 0.000 55.895 0.210 ;
    END
  END r0_rd_out[6]
  PIN r0_rd_out[7]
    DIRECTION OUTPUT ;
    USE SIGNAL ;
    SHAPE ABUTMENT ;
    PORT
      LAYER metal2 ;
      RECT 56.965 0.000 57.035 0.210 ;
    END
  END r0_rd_out[7]
  PIN r0_rd_out[8]
    DIRECTION OUTPUT ;
    USE SIGNAL ;
    SHAPE ABUTMENT ;
    PORT
      LAYER metal2 ;
      RECT 58.105 0.000 58.175 0.210 ;
    END
  END r0_rd_out[8]
  PIN r0_rd_out[9]
    DIRECTION OUTPUT ;
    USE SIGNAL ;
    SHAPE ABUTMENT ;
    PORT
      LAYER metal2 ;
      RECT 59.245 0.000 59.315 0.210 ;
    END
  END r0_rd_out[9]
  PIN r0_rd_out[10]
    DIRECTION OUTPUT ;
    USE SIGNAL ;
    SHAPE ABUTMENT ;
    PORT
      LAYER metal2 ;
      RECT 60.385 0.000 60.455 0.210 ;
    END
  END r0_rd_out[10]
  PIN r0_rd_out[11]
    DIRECTION OUTPUT ;
    USE SIGNAL ;
    SHAPE ABUTMENT ;
    PORT
      LAYER metal2 ;
      RECT 61.525 0.000 61.595 0.210 ;
    END
  END r0_rd_out[11]
  PIN r0_rd_out[12]
    DIRECTION OUTPUT ;
    USE SIGNAL ;
    SHAPE ABUTMENT ;
    PORT
      LAYER metal2 ;
      RECT 62.665 0.000 62.735 0.210 ;
    END
  END r0_rd_out[12]
  PIN r0_rd_out[13]
    DIRECTION OUTPUT ;
    USE SIGNAL ;
    SHAPE ABUTMENT ;
    PORT
      LAYER metal2 ;
      RECT 63.805 0.000 63.875 0.210 ;
    END
  END r0_rd_out[13]
  PIN r0_rd_out[14]
    DIRECTION OUTPUT ;
    USE SIGNAL ;
    SHAPE ABUTMENT ;
    PORT
      LAYER metal2 ;
      RECT 64.945 0.000 65.015 0.210 ;
    END
  END r0_rd_out[14]
  PIN r0_rd_out[15]
    DIRECTION OUTPUT ;
    USE SIGNAL ;
    SHAPE ABUTMENT ;
    PORT
      LAYER metal2 ;
      RECT 66.085 0.000 66.155 0.210 ;
    END
  END r0_rd_out[15]
  PIN r0_rd_out[16]
    DIRECTION OUTPUT ;
    USE SIGNAL ;
    SHAPE ABUTMENT ;
    PORT
      LAYER metal2 ;
      RECT 67.225 0.000 67.295 0.210 ;
    END
  END r0_rd_out[16]
  PIN r0_rd_out[17]
    DIRECTION OUTPUT ;
    USE SIGNAL ;
    SHAPE ABUTMENT ;
    PORT
      LAYER metal2 ;
      RECT 68.365 0.000 68.435 0.210 ;
    END
  END r0_rd_out[17]
  PIN r0_rd_out[18]
    DIRECTION OUTPUT ;
    USE SIGNAL ;
    SHAPE ABUTMENT ;
    PORT
      LAYER metal2 ;
      RECT 69.505 0.000 69.575 0.210 ;
    END
  END r0_rd_out[18]
  PIN r0_rd_out[19]
    DIRECTION OUTPUT ;
    USE SIGNAL ;
    SHAPE ABUTMENT ;
    PORT
      LAYER metal2 ;
      RECT 70.645 0.000 70.715 0.210 ;
    END
  END r0_rd_out[19]
  PIN r0_rd_out[20]
    DIRECTION OUTPUT ;
    USE SIGNAL ;
    SHAPE ABUTMENT ;
    PORT
      LAYER metal2 ;
      RECT 71.785 0.000 71.855 0.210 ;
    END
  END r0_rd_out[20]
  PIN r0_rd_out[21]
    DIRECTION OUTPUT ;
    USE SIGNAL ;
    SHAPE ABUTMENT ;
    PORT
      LAYER metal2 ;
      RECT 72.925 0.000 72.995 0.210 ;
    END
  END r0_rd_out[21]
  PIN r0_rd_out[22]
    DIRECTION OUTPUT ;
    USE SIGNAL ;
    SHAPE ABUTMENT ;
    PORT
      LAYER metal2 ;
      RECT 74.065 0.000 74.135 0.210 ;
    END
  END r0_rd_out[22]
  PIN r0_rd_out[23]
    DIRECTION OUTPUT ;
    USE SIGNAL ;
    SHAPE ABUTMENT ;
    PORT
      LAYER metal2 ;
      RECT 75.205 0.000 75.275 0.210 ;
    END
  END r0_rd_out[23]
  PIN r0_rd_out[24]
    DIRECTION OUTPUT ;
    USE SIGNAL ;
    SHAPE ABUTMENT ;
    PORT
      LAYER metal2 ;
      RECT 76.345 0.000 76.415 0.210 ;
    END
  END r0_rd_out[24]
  PIN r0_rd_out[25]
    DIRECTION OUTPUT ;
    USE SIGNAL ;
    SHAPE ABUTMENT ;
    PORT
      LAYER metal2 ;
      RECT 77.485 0.000 77.555 0.210 ;
    END
  END r0_rd_out[25]
  PIN r0_rd_out[26]
    DIRECTION OUTPUT ;
    USE SIGNAL ;
    SHAPE ABUTMENT ;
    PORT
      LAYER metal2 ;
      RECT 78.625 0.000 78.695 0.210 ;
    END
  END r0_rd_out[26]
  PIN r0_rd_out[27]
    DIRECTION OUTPUT ;
    USE SIGNAL ;
    SHAPE ABUTMENT ;
    PORT
      LAYER metal2 ;
      RECT 79.765 0.000 79.835 0.210 ;
    END
  END r0_rd_out[27]
  PIN r0_rd_out[28]
    DIRECTION OUTPUT ;
    USE SIGNAL ;
    SHAPE ABUTMENT ;
    PORT
      LAYER metal2 ;
      RECT 80.905 0.000 80.975 0.210 ;
    END
  END r0_rd_out[28]
  PIN r0_rd_out[29]
    DIRECTION OUTPUT ;
    USE SIGNAL ;
    SHAPE ABUTMENT ;
    PORT
      LAYER metal2 ;
      RECT 82.045 0.000 82.115 0.210 ;
    END
  END r0_rd_out[29]
  PIN r0_rd_out[30]
    DIRECTION OUTPUT ;
    USE SIGNAL ;
    SHAPE ABUTMENT ;
    PORT
      LAYER metal2 ;
      RECT 83.185 0.000 83.255 0.210 ;
    END
  END r0_rd_out[30]
  PIN r0_rd_out[31]
    DIRECTION OUTPUT ;
    USE SIGNAL ;
    SHAPE ABUTMENT ;
    PORT
      LAYER metal2 ;
      RECT 84.325 0.000 84.395 0.210 ;
    END
  END r0_rd_out[31]
  PIN r0_rd_out[32]
    DIRECTION OUTPUT ;
    USE SIGNAL ;
    SHAPE ABUTMENT ;
    PORT
      LAYER metal2 ;
      RECT 85.465 0.000 85.535 0.210 ;
    END
  END r0_rd_out[32]
  PIN r0_rd_out[33]
    DIRECTION OUTPUT ;
    USE SIGNAL ;
    SHAPE ABUTMENT ;
    PORT
      LAYER metal2 ;
      RECT 86.605 0.000 86.675 0.210 ;
    END
  END r0_rd_out[33]
  PIN r0_rd_out[34]
    DIRECTION OUTPUT ;
    USE SIGNAL ;
    SHAPE ABUTMENT ;
    PORT
      LAYER metal2 ;
      RECT 87.745 0.000 87.815 0.210 ;
    END
  END r0_rd_out[34]
  PIN r0_rd_out[35]
    DIRECTION OUTPUT ;
    USE SIGNAL ;
    SHAPE ABUTMENT ;
    PORT
      LAYER metal2 ;
      RECT 88.885 0.000 88.955 0.210 ;
    END
  END r0_rd_out[35]
  PIN r0_rd_out[36]
    DIRECTION OUTPUT ;
    USE SIGNAL ;
    SHAPE ABUTMENT ;
    PORT
      LAYER metal2 ;
      RECT 90.025 0.000 90.095 0.210 ;
    END
  END r0_rd_out[36]
  PIN r0_rd_out[37]
    DIRECTION OUTPUT ;
    USE SIGNAL ;
    SHAPE ABUTMENT ;
    PORT
      LAYER metal2 ;
      RECT 91.165 0.000 91.235 0.210 ;
    END
  END r0_rd_out[37]
  PIN r0_rd_out[38]
    DIRECTION OUTPUT ;
    USE SIGNAL ;
    SHAPE ABUTMENT ;
    PORT
      LAYER metal2 ;
      RECT 92.305 0.000 92.375 0.210 ;
    END
  END r0_rd_out[38]
  PIN r0_rd_out[39]
    DIRECTION OUTPUT ;
    USE SIGNAL ;
    SHAPE ABUTMENT ;
    PORT
      LAYER metal2 ;
      RECT 93.445 0.000 93.515 0.210 ;
    END
  END r0_rd_out[39]
  PIN r0_rd_out[40]
    DIRECTION OUTPUT ;
    USE SIGNAL ;
    SHAPE ABUTMENT ;
    PORT
      LAYER metal2 ;
      RECT 94.585 0.000 94.655 0.210 ;
    END
  END r0_rd_out[40]
  PIN r0_rd_out[41]
    DIRECTION OUTPUT ;
    USE SIGNAL ;
    SHAPE ABUTMENT ;
    PORT
      LAYER metal2 ;
      RECT 95.725 0.000 95.795 0.210 ;
    END
  END r0_rd_out[41]
  PIN r0_rd_out[42]
    DIRECTION OUTPUT ;
    USE SIGNAL ;
    SHAPE ABUTMENT ;
    PORT
      LAYER metal2 ;
      RECT 96.865 0.000 96.935 0.210 ;
    END
  END r0_rd_out[42]
  PIN r0_rd_out[43]
    DIRECTION OUTPUT ;
    USE SIGNAL ;
    SHAPE ABUTMENT ;
    PORT
      LAYER metal2 ;
      RECT 41.005 120.190 41.075 120.400 ;
    END
  END r0_rd_out[43]
  PIN r0_rd_out[44]
    DIRECTION OUTPUT ;
    USE SIGNAL ;
    SHAPE ABUTMENT ;
    PORT
      LAYER metal2 ;
      RECT 41.955 120.190 42.025 120.400 ;
    END
  END r0_rd_out[44]
  PIN r0_rd_out[45]
    DIRECTION OUTPUT ;
    USE SIGNAL ;
    SHAPE ABUTMENT ;
    PORT
      LAYER metal2 ;
      RECT 42.905 120.190 42.975 120.400 ;
    END
  END r0_rd_out[45]
  PIN r0_rd_out[46]
    DIRECTION OUTPUT ;
    USE SIGNAL ;
    SHAPE ABUTMENT ;
    PORT
      LAYER metal2 ;
      RECT 43.855 120.190 43.925 120.400 ;
    END
  END r0_rd_out[46]
  PIN r0_rd_out[47]
    DIRECTION OUTPUT ;
    USE SIGNAL ;
    SHAPE ABUTMENT ;
    PORT
      LAYER metal2 ;
      RECT 44.805 120.190 44.875 120.400 ;
    END
  END r0_rd_out[47]
  PIN r0_rd_out[48]
    DIRECTION OUTPUT ;
    USE SIGNAL ;
    SHAPE ABUTMENT ;
    PORT
      LAYER metal2 ;
      RECT 45.755 120.190 45.825 120.400 ;
    END
  END r0_rd_out[48]
  PIN r0_rd_out[49]
    DIRECTION OUTPUT ;
    USE SIGNAL ;
    SHAPE ABUTMENT ;
    PORT
      LAYER metal2 ;
      RECT 46.705 120.190 46.775 120.400 ;
    END
  END r0_rd_out[49]
  PIN r0_rd_out[50]
    DIRECTION OUTPUT ;
    USE SIGNAL ;
    SHAPE ABUTMENT ;
    PORT
      LAYER metal2 ;
      RECT 47.655 120.190 47.725 120.400 ;
    END
  END r0_rd_out[50]
  PIN r0_rd_out[51]
    DIRECTION OUTPUT ;
    USE SIGNAL ;
    SHAPE ABUTMENT ;
    PORT
      LAYER metal2 ;
      RECT 48.605 120.190 48.675 120.400 ;
    END
  END r0_rd_out[51]
  PIN r0_rd_out[52]
    DIRECTION OUTPUT ;
    USE SIGNAL ;
    SHAPE ABUTMENT ;
    PORT
      LAYER metal2 ;
      RECT 49.555 120.190 49.625 120.400 ;
    END
  END r0_rd_out[52]
  PIN r0_rd_out[53]
    DIRECTION OUTPUT ;
    USE SIGNAL ;
    SHAPE ABUTMENT ;
    PORT
      LAYER metal2 ;
      RECT 50.505 120.190 50.575 120.400 ;
    END
  END r0_rd_out[53]
  PIN r0_rd_out[54]
    DIRECTION OUTPUT ;
    USE SIGNAL ;
    SHAPE ABUTMENT ;
    PORT
      LAYER metal2 ;
      RECT 51.455 120.190 51.525 120.400 ;
    END
  END r0_rd_out[54]
  PIN r0_rd_out[55]
    DIRECTION OUTPUT ;
    USE SIGNAL ;
    SHAPE ABUTMENT ;
    PORT
      LAYER metal2 ;
      RECT 52.405 120.190 52.475 120.400 ;
    END
  END r0_rd_out[55]
  PIN r0_rd_out[56]
    DIRECTION OUTPUT ;
    USE SIGNAL ;
    SHAPE ABUTMENT ;
    PORT
      LAYER metal2 ;
      RECT 53.355 120.190 53.425 120.400 ;
    END
  END r0_rd_out[56]
  PIN r0_rd_out[57]
    DIRECTION OUTPUT ;
    USE SIGNAL ;
    SHAPE ABUTMENT ;
    PORT
      LAYER metal2 ;
      RECT 54.305 120.190 54.375 120.400 ;
    END
  END r0_rd_out[57]
  PIN r0_rd_out[58]
    DIRECTION OUTPUT ;
    USE SIGNAL ;
    SHAPE ABUTMENT ;
    PORT
      LAYER metal2 ;
      RECT 55.255 120.190 55.325 120.400 ;
    END
  END r0_rd_out[58]
  PIN r0_rd_out[59]
    DIRECTION OUTPUT ;
    USE SIGNAL ;
    SHAPE ABUTMENT ;
    PORT
      LAYER metal2 ;
      RECT 56.205 120.190 56.275 120.400 ;
    END
  END r0_rd_out[59]
  PIN r0_rd_out[60]
    DIRECTION OUTPUT ;
    USE SIGNAL ;
    SHAPE ABUTMENT ;
    PORT
      LAYER metal2 ;
      RECT 57.155 120.190 57.225 120.400 ;
    END
  END r0_rd_out[60]
  PIN r0_rd_out[61]
    DIRECTION OUTPUT ;
    USE SIGNAL ;
    SHAPE ABUTMENT ;
    PORT
      LAYER metal2 ;
      RECT 58.105 120.190 58.175 120.400 ;
    END
  END r0_rd_out[61]
  PIN r0_rd_out[62]
    DIRECTION OUTPUT ;
    USE SIGNAL ;
    SHAPE ABUTMENT ;
    PORT
      LAYER metal2 ;
      RECT 59.055 120.190 59.125 120.400 ;
    END
  END r0_rd_out[62]
  PIN r0_rd_out[63]
    DIRECTION OUTPUT ;
    USE SIGNAL ;
    SHAPE ABUTMENT ;
    PORT
      LAYER metal2 ;
      RECT 60.005 120.190 60.075 120.400 ;
    END
  END r0_rd_out[63]
  PIN r0_rd_out[64]
    DIRECTION OUTPUT ;
    USE SIGNAL ;
    SHAPE ABUTMENT ;
    PORT
      LAYER metal2 ;
      RECT 60.955 120.190 61.025 120.400 ;
    END
  END r0_rd_out[64]
  PIN r0_rd_out[65]
    DIRECTION OUTPUT ;
    USE SIGNAL ;
    SHAPE ABUTMENT ;
    PORT
      LAYER metal2 ;
      RECT 61.905 120.190 61.975 120.400 ;
    END
  END r0_rd_out[65]
  PIN r0_rd_out[66]
    DIRECTION OUTPUT ;
    USE SIGNAL ;
    SHAPE ABUTMENT ;
    PORT
      LAYER metal2 ;
      RECT 62.855 120.190 62.925 120.400 ;
    END
  END r0_rd_out[66]
  PIN r0_rd_out[67]
    DIRECTION OUTPUT ;
    USE SIGNAL ;
    SHAPE ABUTMENT ;
    PORT
      LAYER metal2 ;
      RECT 63.805 120.190 63.875 120.400 ;
    END
  END r0_rd_out[67]
  PIN r0_rd_out[68]
    DIRECTION OUTPUT ;
    USE SIGNAL ;
    SHAPE ABUTMENT ;
    PORT
      LAYER metal2 ;
      RECT 64.755 120.190 64.825 120.400 ;
    END
  END r0_rd_out[68]
  PIN r0_rd_out[69]
    DIRECTION OUTPUT ;
    USE SIGNAL ;
    SHAPE ABUTMENT ;
    PORT
      LAYER metal2 ;
      RECT 65.705 120.190 65.775 120.400 ;
    END
  END r0_rd_out[69]
  PIN r0_rd_out[70]
    DIRECTION OUTPUT ;
    USE SIGNAL ;
    SHAPE ABUTMENT ;
    PORT
      LAYER metal2 ;
      RECT 66.655 120.190 66.725 120.400 ;
    END
  END r0_rd_out[70]
  PIN r0_rd_out[71]
    DIRECTION OUTPUT ;
    USE SIGNAL ;
    SHAPE ABUTMENT ;
    PORT
      LAYER metal2 ;
      RECT 67.605 120.190 67.675 120.400 ;
    END
  END r0_rd_out[71]
  PIN r0_rd_out[72]
    DIRECTION OUTPUT ;
    USE SIGNAL ;
    SHAPE ABUTMENT ;
    PORT
      LAYER metal2 ;
      RECT 68.555 120.190 68.625 120.400 ;
    END
  END r0_rd_out[72]
  PIN r0_rd_out[73]
    DIRECTION OUTPUT ;
    USE SIGNAL ;
    SHAPE ABUTMENT ;
    PORT
      LAYER metal2 ;
      RECT 69.505 120.190 69.575 120.400 ;
    END
  END r0_rd_out[73]
  PIN r0_rd_out[74]
    DIRECTION OUTPUT ;
    USE SIGNAL ;
    SHAPE ABUTMENT ;
    PORT
      LAYER metal2 ;
      RECT 70.455 120.190 70.525 120.400 ;
    END
  END r0_rd_out[74]
  PIN r0_rd_out[75]
    DIRECTION OUTPUT ;
    USE SIGNAL ;
    SHAPE ABUTMENT ;
    PORT
      LAYER metal2 ;
      RECT 71.405 120.190 71.475 120.400 ;
    END
  END r0_rd_out[75]
  PIN r0_rd_out[76]
    DIRECTION OUTPUT ;
    USE SIGNAL ;
    SHAPE ABUTMENT ;
    PORT
      LAYER metal2 ;
      RECT 72.355 120.190 72.425 120.400 ;
    END
  END r0_rd_out[76]
  PIN r0_rd_out[77]
    DIRECTION OUTPUT ;
    USE SIGNAL ;
    SHAPE ABUTMENT ;
    PORT
      LAYER metal2 ;
      RECT 73.305 120.190 73.375 120.400 ;
    END
  END r0_rd_out[77]
  PIN r0_rd_out[78]
    DIRECTION OUTPUT ;
    USE SIGNAL ;
    SHAPE ABUTMENT ;
    PORT
      LAYER metal2 ;
      RECT 74.255 120.190 74.325 120.400 ;
    END
  END r0_rd_out[78]
  PIN r0_rd_out[79]
    DIRECTION OUTPUT ;
    USE SIGNAL ;
    SHAPE ABUTMENT ;
    PORT
      LAYER metal2 ;
      RECT 75.205 120.190 75.275 120.400 ;
    END
  END r0_rd_out[79]
  PIN r0_rd_out[80]
    DIRECTION OUTPUT ;
    USE SIGNAL ;
    SHAPE ABUTMENT ;
    PORT
      LAYER metal2 ;
      RECT 76.155 120.190 76.225 120.400 ;
    END
  END r0_rd_out[80]
  PIN r0_rd_out[81]
    DIRECTION OUTPUT ;
    USE SIGNAL ;
    SHAPE ABUTMENT ;
    PORT
      LAYER metal2 ;
      RECT 77.105 120.190 77.175 120.400 ;
    END
  END r0_rd_out[81]
  PIN r0_rd_out[82]
    DIRECTION OUTPUT ;
    USE SIGNAL ;
    SHAPE ABUTMENT ;
    PORT
      LAYER metal2 ;
      RECT 78.055 120.190 78.125 120.400 ;
    END
  END r0_rd_out[82]
  PIN r0_rd_out[83]
    DIRECTION OUTPUT ;
    USE SIGNAL ;
    SHAPE ABUTMENT ;
    PORT
      LAYER metal2 ;
      RECT 79.005 120.190 79.075 120.400 ;
    END
  END r0_rd_out[83]
  PIN r0_rd_out[84]
    DIRECTION OUTPUT ;
    USE SIGNAL ;
    SHAPE ABUTMENT ;
    PORT
      LAYER metal2 ;
      RECT 79.955 120.190 80.025 120.400 ;
    END
  END r0_rd_out[84]
  PIN w0_addr_in[0]
    DIRECTION INPUT ;
    USE SIGNAL ;
    SHAPE ABUTMENT ;
    PORT
      LAYER metal3 ;
      RECT 0.000 105.525 0.210 105.595 ;
    END
  END w0_addr_in[0]
  PIN w0_addr_in[1]
    DIRECTION INPUT ;
    USE SIGNAL ;
    SHAPE ABUTMENT ;
    PORT
      LAYER metal3 ;
      RECT 0.000 107.905 0.210 107.975 ;
    END
  END w0_addr_in[1]
  PIN w0_addr_in[2]
    DIRECTION INPUT ;
    USE SIGNAL ;
    SHAPE ABUTMENT ;
    PORT
      LAYER metal3 ;
      RECT 0.000 110.285 0.210 110.355 ;
    END
  END w0_addr_in[2]
  PIN w0_addr_in[3]
    DIRECTION INPUT ;
    USE SIGNAL ;
    SHAPE ABUTMENT ;
    PORT
      LAYER metal3 ;
      RECT 103.910 100.765 104.120 100.835 ;
    END
  END w0_addr_in[3]
  PIN r0_addr_in[0]
    DIRECTION INPUT ;
    USE SIGNAL ;
    SHAPE ABUTMENT ;
    PORT
      LAYER metal3 ;
      RECT 0.000 112.665 0.210 112.735 ;
    END
  END r0_addr_in[0]
  PIN r0_addr_in[1]
    DIRECTION INPUT ;
    USE SIGNAL ;
    SHAPE ABUTMENT ;
    PORT
      LAYER metal3 ;
      RECT 0.000 115.045 0.210 115.115 ;
    END
  END r0_addr_in[1]
  PIN r0_addr_in[2]
    DIRECTION INPUT ;
    USE SIGNAL ;
    SHAPE ABUTMENT ;
    PORT
      LAYER metal3 ;
      RECT 0.000 117.425 0.210 117.495 ;
    END
  END r0_addr_in[2]
  PIN r0_addr_in[3]
    DIRECTION INPUT ;
    USE SIGNAL ;
    SHAPE ABUTMENT ;
    PORT
      LAYER metal3 ;
      RECT 103.910 107.905 104.120 107.975 ;
    END
  END r0_addr_in[3]
  PIN w0_we_in
    DIRECTION INPUT ;
    USE SIGNAL ;
    SHAPE ABUTMENT ;
    PORT
      LAYER metal2 ;
      RECT 80.905 120.190 80.975 120.400 ;
    END
  END w0_we_in
  PIN w0_ce_in
    DIRECTION INPUT ;
    USE SIGNAL ;
    SHAPE ABUTMENT ;
    PORT
      LAYER metal2 ;
      RECT 81.855 120.190 81.925 120.400 ;
    END
  END w0_ce_in
  PIN w0_clk
    DIRECTION INPUT ;
    USE SIGNAL ;
    SHAPE ABUTMENT ;
    PORT
      LAYER metal2 ;
      RECT 82.805 120.190 82.875 120.400 ;
    END
  END w0_clk
  PIN r0_ce_in
    DIRECTION INPUT ;
    USE SIGNAL ;
    SHAPE ABUTMENT ;
    PORT
      LAYER metal2 ;
      RECT 83.755 120.190 83.825 120.400 ;
    END
  END r0_ce_in
  PIN r0_clk
    DIRECTION INPUT ;
    USE SIGNAL ;
    SHAPE ABUTMENT ;
    PORT
      LAYER metal2 ;
      RECT 84.705 120.190 84.775 120.400 ;
    END
  END r0_clk
  PIN VSS
    DIRECTION INOUT ;
    USE GROUND ;
    PORT
      LAYER metal4 ;
      RECT 1.000 0.840 1.280 119.560 ;
      RECT 3.240 0.840 3.520 119.560 ;
      RECT 5.480 0.840 5.760 119.560 ;
      RECT 7.720 0.840 8.000 119.560 ;
      RECT 9.960 0.840 10.240 119.560 ;
      RECT 12.200 0.840 12.480 119.560 ;
      RECT 14.440 0.840 14.720 119.560 ;
      RECT 16.680 0.840 16.960 119.560 ;
      RECT 18.920 0.840 19.200 119.560 ;
      RECT 21.160 0.840 21.440 119.560 ;
      RECT 23.400 0.840 23.680 119.560 ;
      RECT 25.640 0.840 25.920 119.560 ;
      RECT 27.880 0.840 28.160 119.560 ;
      RECT 30.120 0.840 30.400 119.560 ;
      RECT 32.360 0.840 32.640 119.560 ;
      RECT 34.600 0.840 34.880 119.560 ;
      RECT 36.840 0.840 37.120 119.560 ;
      RECT 39.080 0.840 39.360 119.560 ;
      RECT 41.320 0.840 41.600 119.560 ;
      RECT 43.560 0.840 43.840 119.560 ;
      RECT 45.800 0.840 46.080 119.560 ;
      RECT 48.040 0.840 48.320 119.560 ;
      RECT 50.280 0.840 50.560 119.560 ;
      RECT 52.520 0.840 52.800 119.560 ;
      RECT 54.760 0.840 55.040 119.560 ;
      RECT 57.000 0.840 57.280 119.560 ;
      RECT 59.240 0.840 59.520 119.560 ;
      RECT 61.480 0.840 61.760 119.560 ;
      RECT 63.720 0.840 64.000 119.560 ;
      RECT 65.960 0.840 66.240 119.560 ;
      RECT 68.200 0.840 68.480 119.560 ;
      RECT 70.440 0.840 70.720 119.560 ;
      RECT 72.680 0.840 72.960 119.560 ;
      RECT 74.920 0.840 75.200 119.560 ;
      RECT 77.160 0.840 77.440 119.560 ;
      RECT 79.400 0.840 79.680 119.560 ;
      RECT 81.640 0.840 81.920 119.560 ;
      RECT 83.880 0.840 84.160 119.560 ;
      RECT 86.120 0.840 86.400 119.560 ;
      RECT 88.360 0.840 88.640 119.560 ;
      RECT 90.600 0.840 90.880 119.560 ;
      RECT 92.840 0.840 93.120 119.560 ;
      RECT 95.080 0.840 95.360 119.560 ;
      RECT 97.320 0.840 97.600 119.560 ;
      RECT 99.560 0.840 99.840 119.560 ;
      RECT 101.800 0.840 102.080 119.560 ;
    END
  END VSS
  PIN VDD
    DIRECTION INOUT ;
    USE POWER ;
    PORT
      LAYER metal4 ;
      RECT 1.000 0.840 1.280 119.560 ;
      RECT 3.240 0.840 3.520 119.560 ;
      RECT 5.480 0.840 5.760 119.560 ;
      RECT 7.720 0.840 8.000 119.560 ;
      RECT 9.960 0.840 10.240 119.560 ;
      RECT 12.200 0.840 12.480 119.560 ;
      RECT 14.440 0.840 14.720 119.560 ;
      RECT 16.680 0.840 16.960 119.560 ;
      RECT 18.920 0.840 19.200 119.560 ;
      RECT 21.160 0.840 21.440 119.560 ;
      RECT 23.400 0.840 23.680 119.560 ;
      RECT 25.640 0.840 25.920 119.560 ;
      RECT 27.880 0.840 28.160 119.560 ;
      RECT 30.120 0.840 30.400 119.560 ;
      RECT 32.360 0.840 32.640 119.560 ;
      RECT 34.600 0.840 34.880 119.560 ;
      RECT 36.840 0.840 37.120 119.560 ;
      RECT 39.080 0.840 39.360 119.560 ;
      RECT 41.320 0.840 41.600 119.560 ;
      RECT 43.560 0.840 43.840 119.560 ;
      RECT 45.800 0.840 46.080 119.560 ;
      RECT 48.040 0.840 48.320 119.560 ;
      RECT 50.280 0.840 50.560 119.560 ;
      RECT 52.520 0.840 52.800 119.560 ;
      RECT 54.760 0.840 55.040 119.560 ;
      RECT 57.000 0.840 57.280 119.560 ;
      RECT 59.240 0.840 59.520 119.560 ;
      RECT 61.480 0.840 61.760 119.560 ;
      RECT 63.720 0.840 64.000 119.560 ;
      RECT 65.960 0.840 66.240 119.560 ;
      RECT 68.200 0.840 68.480 119.560 ;
      RECT 70.440 0.840 70.720 119.560 ;
      RECT 72.680 0.840 72.960 119.560 ;
      RECT 74.920 0.840 75.200 119.560 ;
      RECT 77.160 0.840 77.440 119.560 ;
      RECT 79.400 0.840 79.680 119.560 ;
      RECT 81.640 0.840 81.920 119.560 ;
      RECT 83.880 0.840 84.160 119.560 ;
      RECT 86.120 0.840 86.400 119.560 ;
      RECT 88.360 0.840 88.640 119.560 ;
      RECT 90.600 0.840 90.880 119.560 ;
      RECT 92.840 0.840 93.120 119.560 ;
      RECT 95.080 0.840 95.360 119.560 ;
      RECT 97.320 0.840 97.600 119.560 ;
      RECT 99.560 0.840 99.840 119.560 ;
      RECT 101.800 0.840 102.080 119.560 ;
    END
  END VDD
  OBS
    LAYER metal1 ;
    RECT 0 0 104.120 120.400 ;
    LAYER metal2 ;
    RECT 0 0 104.120 120.400 ;
    LAYER metal3 ;
    RECT 0 0 104.120 120.400 ;
    LAYER metal4 ;
    RECT 0 0 104.120 120.400 ;
    LAYER OVERLAP ;
    RECT 0 0 104.120 120.400 ;
  END
END fakeram_85x16_1r1w

END LIBRARY
